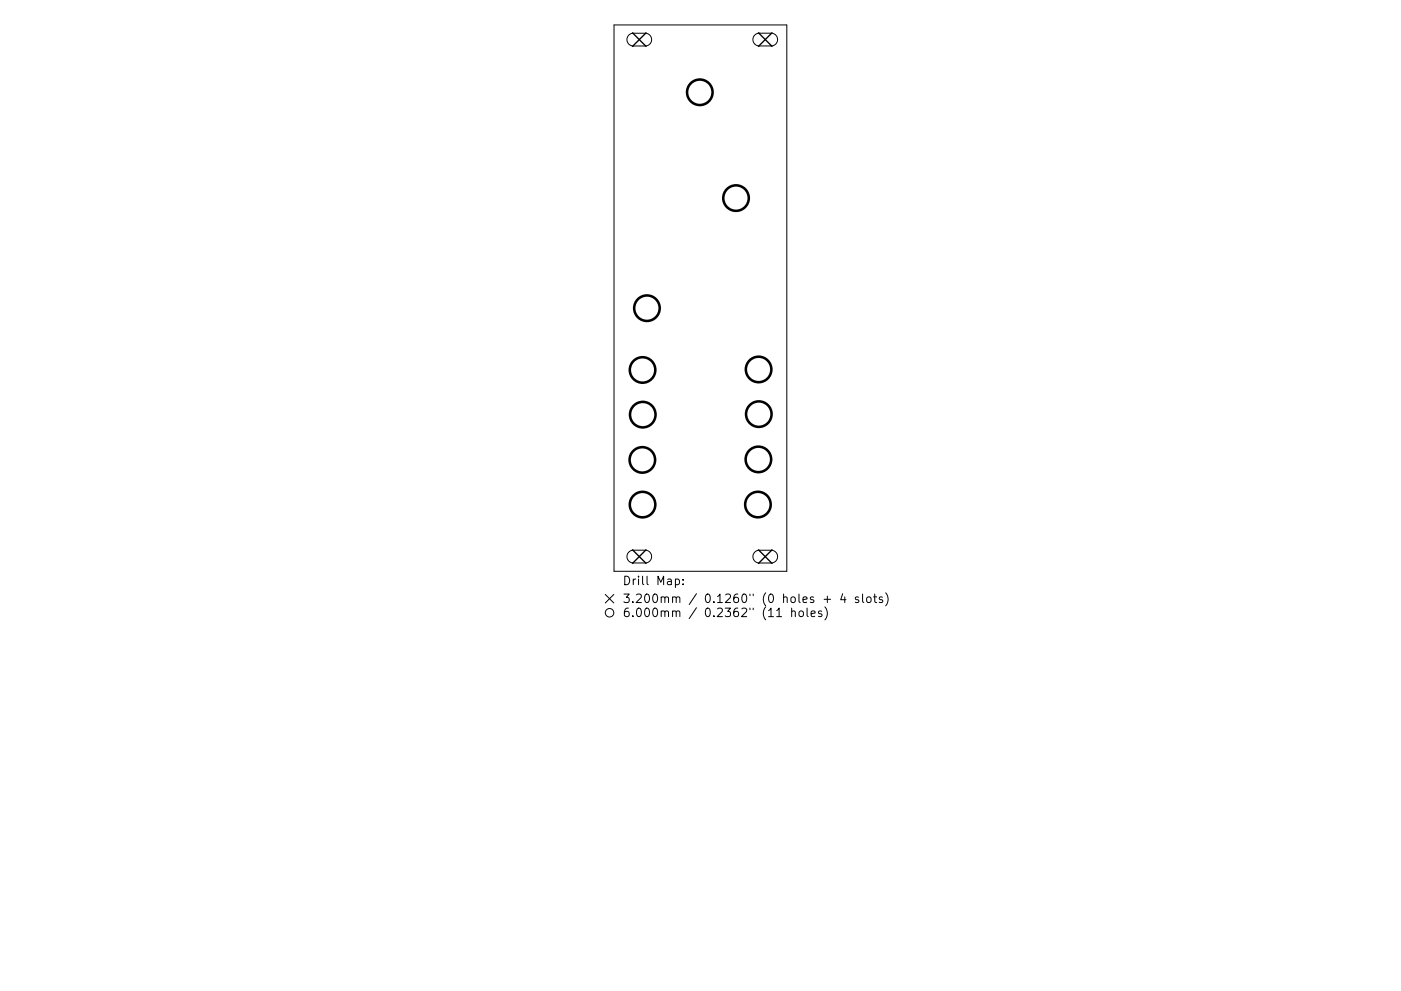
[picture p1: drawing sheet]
<svg xmlns="http://www.w3.org/2000/svg" width="297mm" height="210mm" viewBox="0 0 297 210" stroke-linecap="round" stroke-linejoin="round" font-family="sans-serif">
<defs><g id="words">
<g font-size="2.5">
<text x="131.9" y="124.1">Drill Map:</text>
<text x="131.9" y="127.9">3.200mm / 0.1260&quot; (0 holes + 4 slots)</text>
<text x="131.9" y="130.9">6.000mm / 0.2362&quot; (11 holes)</text>
</g>
</g></defs>
<g fill="none" stroke="#000" stroke-width=".21">
<path d="M130.2 5.3h36.6v115.9h-36.6zM133.3 7.4l.9-.3h2.6a1.35 1.35 0 0 1 1.4 1.3 1.35 1.35 0 0 1-1.4 1.4h-2.5a1.35 1.35 0 0 1-1.3-.9 1.35 1.35 0 0 1 .3-1.5zM160 7.4l.9-.4h2.6a1.35 1.35 0 0 1 1.4 1.4 1.35 1.35 0 0 1-1.4 1.3h-2.5a1.35 1.35 0 0 1-1.3-.8 1.35 1.35 0 0 1 .3-1.5zM133.3 117.1l.9-.4h2.6a1.35 1.35 0 0 1 1.4 1.4 1.35 1.35 0 0 1-1.4 1.3h-2.5a1.35 1.35 0 0 1-1.3-.8 1.35 1.35 0 0 1 .3-1.5zM160 117.1l.9-.4h2.6a1.35 1.35 0 0 1 1.4 1.4 1.35 1.35 0 0 1-1.4 1.3h-2.5a1.35 1.35 0 0 1-1.3-.8 1.35 1.35 0 0 1 .3-1.5zM128.3 126.1l1.8 1.8M130.1 126.1l-1.8 1.8M143.2 122.9h.5l.4 .3v.5l-.2 .3h-.7M144.8 123.9v.2M144.8 122.9v.2M164.7 130.8h1M167.9 129.8l.2-.2 .4 .1 .1 1.1"/>
<path d="M167.9 129v1.8M169.6 129.7l.4-.1 .3 .4v.5l-.3 .3-.4-.1-.2-.2v-.5zM171.1 129v1.6l.3 .2M172 130.2l.8-.1-.1-.4-.5-.1-.2 .3 .1 .8h.6M174.2 129.7l-.4-.1-.3 .3 .1 .2 .6 .2v.4h-.7M174.7 127.2h1.4M174.9 128.8a2.07 2.07 0 0 1 0 2.7M175.4 126.5v1.3M178.7 126l-.5 1.2h1.2M179.1 126.6v1.2M182 126.7l-.4-.1-.3 .3 .1 .3 .6 .1v.5h-.7M182.9 126v1.6l.2 .2"/>
<path d="M183.9 126.7l.4-.1 .4 .4v.5l-.4 .3h-.4l-.2-.3v-.5zM185.2 126.6h.7M185.5 126v1.6l.4 .2M187.1 126.7l-.4-.1-.3 .3 .1 .3 .6 .1v.5h-.7M187.8 125.8a2.07 2.07 0 0 1 0 2.7"/>
<circle cx="129.2" cy="130" r=".9"/>
</g>
<path d="M134.1 7l2.9 2.8M137 7l-2.9 2.8M160.8 7l2.9 2.8M163.7 7l-2.9 2.8M134.1 116.6l2.9 2.9M137 116.6l-2.9 2.9M160.8 116.7l2.9 2.8M163.7 116.7l-2.9 2.8" fill="none" stroke="#000" stroke-width=".29"/>
<g fill="none" stroke="#000" stroke-width=".54">
<circle cx="148.4" cy="19.6" r="2.71"/>
<circle cx="156" cy="42" r="2.71"/>
<circle cx="136.2" cy="78.5" r="2.71"/>
<circle cx="137.2" cy="65.4" r="2.71"/>
<circle cx="160.8" cy="78.4" r="2.71"/>
<circle cx="136.2" cy="97.6" r="2.71"/>
<circle cx="136.3" cy="88" r="2.71"/>
<circle cx="160.8" cy="97.5" r="2.71"/>
<circle cx="160.9" cy="87.9" r="2.71"/>
<circle cx="136.2" cy="107.1" r="2.71"/>
<circle cx="160.7" cy="107" r="2.71"/>
</g>
<use href="#words"/>
</svg>
